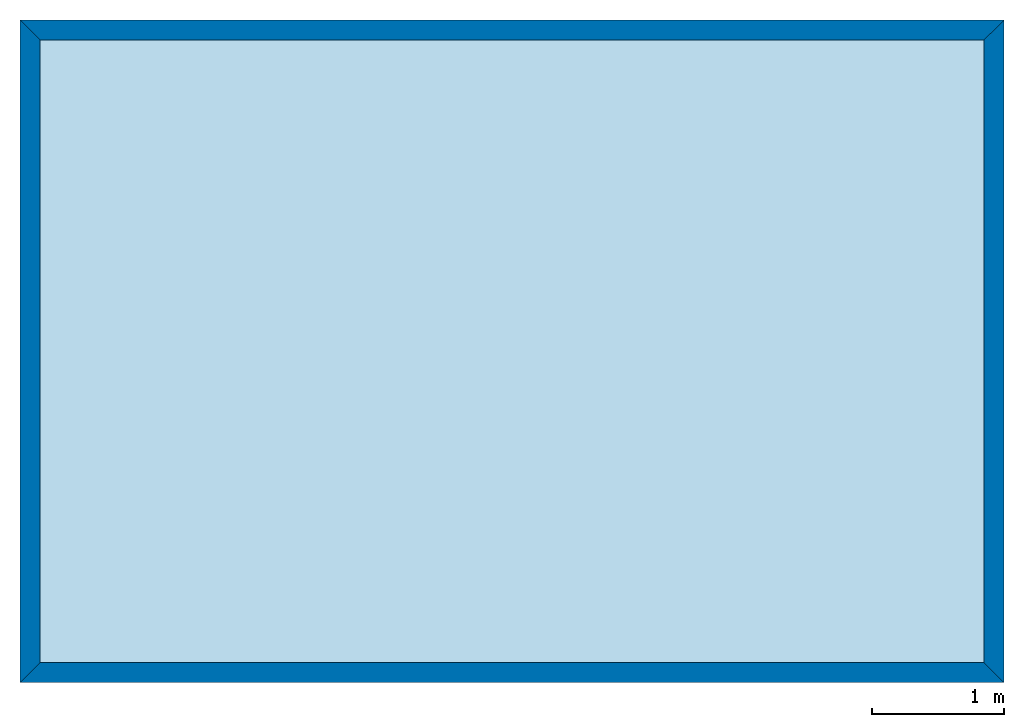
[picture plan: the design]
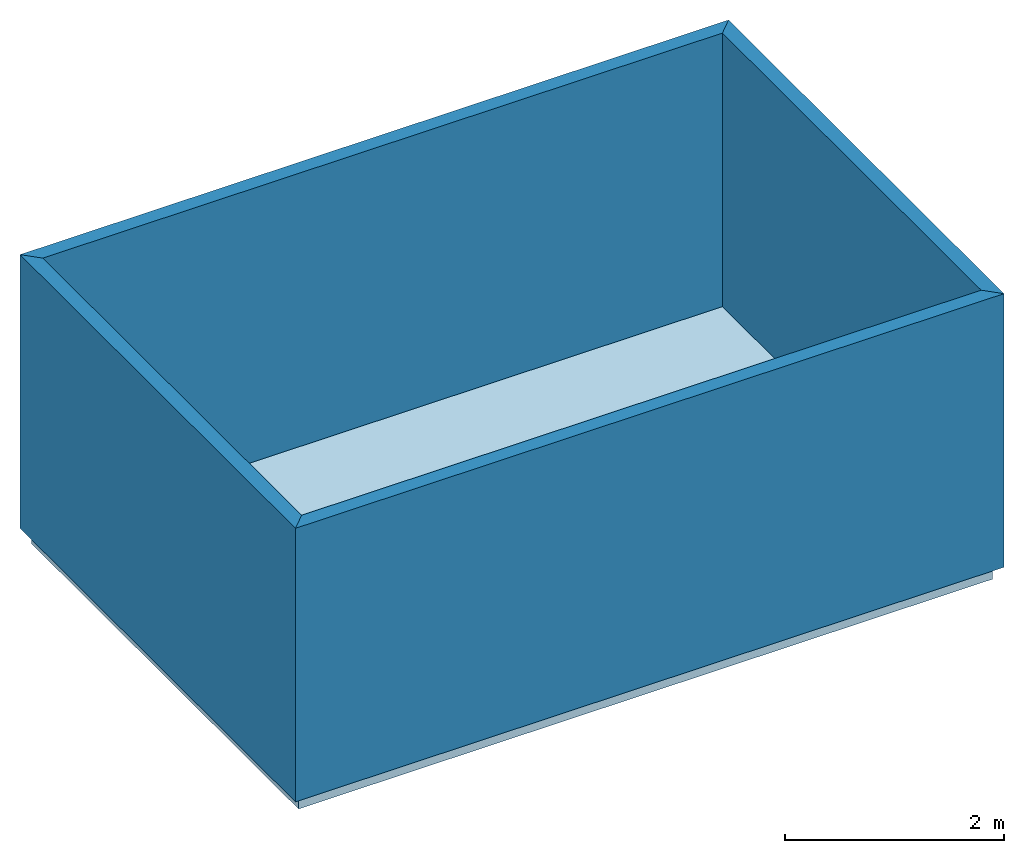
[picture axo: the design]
# One storey: 4 walls, 1 slab.
"""IFC4 building model written with IfcOpenShell, lengths in inches."""

from ifc_helpers import new_model, entity, si_unit, converted_unit, frame, origin, place, context, project, spatial, polyline, outline, extrude, material, layer, layer_set, layer_usage, element, save


model = new_model("IFC4")

# Units and contexts
model_context = context("Model", 3, precision=1e-05, world=origin())
plan_context = context("Plan", 2, precision=1e-05, world=origin())
ifc_project = project(units=[converted_unit("LENGTHUNIT", "inch", entity("IfcLengthMeasure", 0.0254), si_unit("LENGTHUNIT", "METRE"), dimensions=[1, 0, 0, 0, 0, 0, 0])], contexts=[model_context, plan_context])

# Site, building, storey
site_placement = place(None, origin())
site = spatial("IfcSite", under=ifc_project, at=site_placement, CompositionType="ELEMENT")
building_placement = place(site_placement, frame((576.0, 240.0, 48.0)))
building = spatial("IfcBuilding", under=site, at=building_placement, Name="Building #1", CompositionType="ELEMENT")
storey_placement = place(building_placement, origin())
storey = spatial("IfcBuildingStorey", under=building, at=storey_placement, Name="Ground Level", CompositionType="ELEMENT", Elevation=0.0)

# Slab
ifc_material = material(Name="Concrete (Nominal)", Category="Concrete")
ifc_layer = layer(ifc_material, 6.0, Name="Core")
ifc_layer_set = layer_set([ifc_layer])
ifc_layer_usage = layer_usage(ifc_layer_set, "AXIS3", "POSITIVE", 0.0)
slab_placement = place(storey_placement, origin())
element("IfcSlab", 1, at=slab_placement, inside=storey, material=ifc_layer_usage, Name="Slab #1", PredefinedType="BASESLAB", context=model_context, shape_type="SweptSolid", body=[
    extrude(outline(polyline([(0.0, 0.0), (288.0, 0.0), (288.0, 192.0), (0.0, 192.0), (0.0, 0.0)])), origin(), (0.0, 0.0, 1.0), 6.0),
])

# Walls
wall_1_placement = place(storey_placement, frame((0.0, 0.0, 6.0), z_axis=(0.0, 0.0, 1.0), x_axis=(0.0, 1.0, 0.0)))
element("IfcWall", 2, at=wall_1_placement, inside=storey, Name="Wall #1", PredefinedType="NOTDEFINED", context=model_context, shape_type="SweptSolid", body=[
    extrude(outline(polyline([(3.0, -3.0), (189.0, -3.0), (195.0, 3.0), (-3.0, 3.0), (3.0, -3.0)])), origin(), (0.0, 0.0, 1.0), 120.0),
])
wall_2_placement = place(storey_placement, frame((0.0, 192.0, 6.0), z_axis=(0.0, 0.0, 1.0), x_axis=(1.0, 0.0, 0.0)))
element("IfcWall", 3, at=wall_2_placement, inside=storey, Name="Wall #2", PredefinedType="NOTDEFINED", context=model_context, shape_type="SweptSolid", body=[
    extrude(outline(polyline([(3.0, -3.0), (285.0, -3.0), (291.0, 3.0), (-3.0, 3.0), (3.0, -3.0)])), origin(), (0.0, 0.0, 1.0), 120.0),
])
wall_3_placement = place(storey_placement, frame((288.0, 192.0, 6.0), z_axis=(0.0, 0.0, 1.0), x_axis=(0.0, -1.0, 0.0)))
element("IfcWall", 4, at=wall_3_placement, inside=storey, Name="Wall #3", PredefinedType="NOTDEFINED", context=model_context, shape_type="SweptSolid", body=[
    extrude(outline(polyline([(3.0, -3.0), (189.0, -3.0), (195.0, 3.0), (-3.0, 3.0), (3.0, -3.0)])), origin(), (0.0, 0.0, 1.0), 120.0),
])
wall_4_placement = place(storey_placement, frame((288.0, 0.0, 6.0), z_axis=(0.0, 0.0, 1.0), x_axis=(-1.0, 0.0, 0.0)))
element("IfcWall", 5, at=wall_4_placement, inside=storey, Name="Wall #4", PredefinedType="NOTDEFINED", context=model_context, shape_type="SweptSolid", body=[
    extrude(outline(polyline([(3.0, -3.0), (285.0, -3.0), (291.0, 3.0), (-3.0, 3.0), (3.0, -3.0)])), origin(), (0.0, 0.0, 1.0), 120.0),
])

save(model, "model.ifc")
